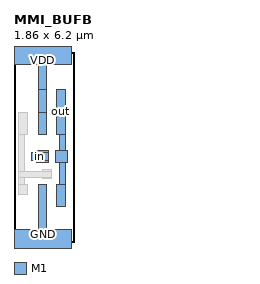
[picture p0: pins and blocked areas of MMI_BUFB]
MACRO MMI_BUFB
	CLASS CORE ;
	FOREIGN MMI_BUFB 0 0 ;
	SIZE 1.86 BY 6.2 ;
	SYMMETRY X Y ;
	SITE CORE1 ;
	PIN out
		DIRECTION output ;
		USE SIGNAL ;
		PORT
			LAYER M1 ;
			RECT 1.385 3.52 1.665 4.99 ;
			LAYER M1 ;
			RECT 1.475 2.98 1.665 3.52 ;
			LAYER M1 ;
			RECT 1.36 2.6 1.74 2.98 ;
			LAYER M1 ;
			RECT 1.475 1.865 1.665 2.6 ;
			LAYER M1 ;
			RECT 1.385 1.165 1.665 1.865 ;
		END
		AntennaDiffArea 0.91245 ;
	END out
	PIN GND
		DIRECTION inout ;
		USE GROUND ;
		PORT
			LAYER M1 ;
			RECT 0.795 0.42 1.075 1.865 ;
			LAYER M1 ;
			RECT 0 -0.42 1.86 0.42 ;
		END
	END GND
	PIN VDD
		DIRECTION inout ;
		USE POWER ;
		PORT
			LAYER M1 ;
			RECT 0 5.78 1.86 6.62 ;
			LAYER M1 ;
			RECT 0.79 4.99 1.07 5.78 ;
			LAYER M1 ;
			RECT 0.79 4.225 1.075 4.99 ;
			LAYER M1 ;
			RECT 0.795 3.52 1.075 4.225 ;
		END
	END VDD
	PIN in
		DIRECTION input ;
		USE SIGNAL ;
		PORT
			LAYER M1 ;
			RECT 0.74 2.93 1.12 2.98 ;
			LAYER M1 ;
			RECT 0.555 2.65 1.12 2.93 ;
			LAYER M1 ;
			RECT 0.74 2.6 1.12 2.65 ;
		END
		AntennaGateArea 0.17325 ;
	END in
	OBS
		LAYER M1 ;
		RECT 0.16 3.52 0.44 4.22 ;
		LAYER M1 ;
		RECT 0.16 2.31 0.355 3.52 ;
		LAYER M1 ;
		RECT 0.935 2.31 1.215 2.35 ;
		LAYER M1 ;
		RECT 0.16 2.115 1.215 2.31 ;
		LAYER M1 ;
		RECT 0.16 1.865 0.355 2.115 ;
		LAYER M1 ;
		RECT 0.935 2.07 1.215 2.115 ;
		LAYER M1 ;
		RECT 0.16 1.55 0.44 1.865 ;
	END
END MMI_BUFB
